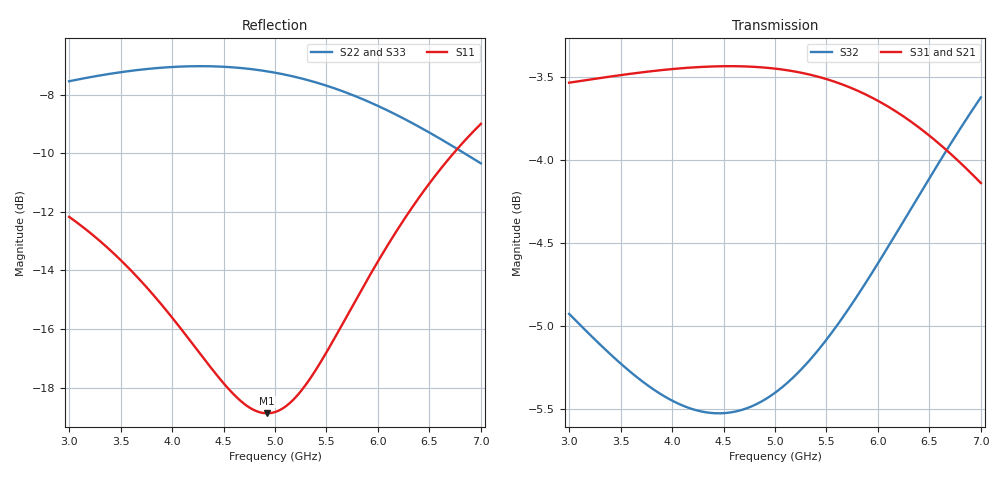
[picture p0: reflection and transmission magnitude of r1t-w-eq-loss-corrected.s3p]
! yapnr Order 0 prediction r1t-w-eq: predictions/references/r1t-w-eq/coarse_dense.s3p, loss-corrected
! substrate W-eq; coupon model OSHPARK-4L-FR408HR; correction: path [('line', 10.75), ('line', 11.0)] (3.0 mm line's Δα)
! |S21|, |S31| (and S12, S13) scaled, phases kept; 50 ohm, e^(+jwt)
# GHz S RI R 50
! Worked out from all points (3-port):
!   161 points, 3 GHz to 7 GHz, reference 50 ohm
!   strongest paths, dB at 3 GHz, 4 GHz, 5 GHz, 6 GHz, 7 GHz:
!     S31: -3.5, -3.4, -3.4, -3.6, -4.1
!     S21: -3.5, -3.4, -3.4, -3.6, -4.1
!     S32: -4.9, -5.4, -5.4, -4.6, -3.6
!   lowest |S11| = -18.9 dB at 4.925 GHz (marker M1), VSWR 1.26, Z = 61.3 + j5.78 ohm
!   |S11| at or under -10 dB: start of sweep to 6.735 GHz
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3  -0.1411 0.2018  -0.3181 -0.5859  -0.3181 -0.5859
   -0.3177 -0.5852  0.1837 0.3771  -0.4298 -0.37
   -0.3177 -0.5852  -0.4298 -0.37  0.1837 0.3771
3.5  -0.0711 0.1953  -0.5094 -0.4361  -0.5094 -0.4361
     -0.5081 -0.4358  0.3311 0.2816  -0.5171 -0.1811
     -0.5081 -0.4358  -0.5171 -0.1811  0.3311 0.2816
4.025  0.00249 0.1637  -0.6401 -0.2095  -0.6401 -0.2095
       -0.6385 -0.2105  0.4287 0.1154  -0.5331 0.0213
       -0.6385 -0.2105  -0.5331 0.0213  0.4287 0.1154
4.475  0.0594 0.1152  -0.674 0.0174  -0.674 0.0174
       -0.6734 0.015  0.4412 -0.0523  -0.4967 0.183
       -0.6734 0.015  -0.4967 0.183  0.4412 -0.0523
4.925  0.1038 0.0466  -0.6262 0.2452  -0.6262 0.2452
       -0.6277 0.2423  0.3831 -0.2084  -0.4215 0.3293
       -0.6277 0.2423  -0.4215 0.3293  0.3831 -0.2084
5  0.1094 0.0333  -0.6103 0.2811  -0.6103 0.2811
   -0.6122 0.2783  0.3673 -0.231  -0.4053 0.352
   -0.6122 0.2783  -0.4053 0.352  0.3673 -0.231
5.55  0.1278 -0.078  -0.4321 0.5047  -0.4321 0.5047
      -0.4363 0.5043  0.2142 -0.3491  -0.2515 0.5
      -0.4363 0.5043  -0.2515 0.5  0.2142 -0.3491
6.05  0.0997 -0.1892  -0.2008 0.6204  -0.2008 0.6204
      -0.2046 0.6236  0.0526 -0.3735  -0.0548 0.5882
      -0.2046 0.6236  -0.0548 0.5882  0.0526 -0.3735
6.55  0.0211 -0.2877  0.0519 0.6325  0.0519 0.6325
      0.0515 0.6379  -0.0881 -0.3273  0.1863 0.5985
      0.0515 0.6379  0.1863 0.5985  -0.0881 -0.3273
7  -0.0876 -0.3439  0.2592 0.5585  0.2592 0.5585
   0.2623 0.5629  -0.177 -0.2469  0.4112 0.5152
   0.2623 0.5629  0.4112 0.5152  -0.177 -0.2469
